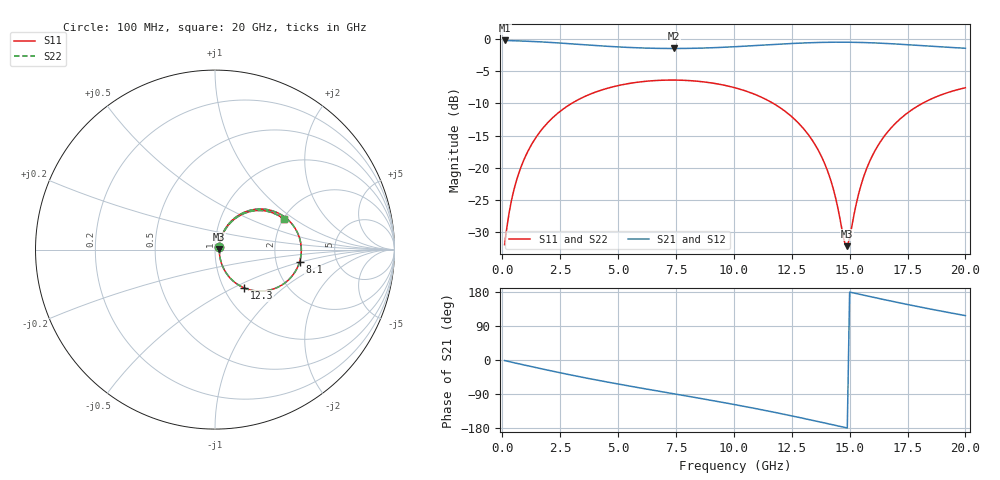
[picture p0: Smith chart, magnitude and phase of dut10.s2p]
! Touchstone file exported from HFSS 2026.1.0
!  File:  C:/ffzhzh/LocalFiles/Ansys_Project_Files/temp_test_TSV_RDL_10_1782979604_6388.aedt
!  Generated:  04:17:51 PM Jul  2, 2026
!  Design:  TSV_RDL
!  Project:  temp_test_TSV_RDL_10_1782979604_6388
! Variables:
!  h_bsmrdl = 3.76um
!  h_ox = 20um
!  h_rdl = 5um
!  h_sub = 52.51um
!  h_tmrdl = 3.14um
!  h_tsv = 52.51um
!  h_via = 3um
!  l_bsmrdl = 600.43um
!  l_sub = 4305.38um
!  l_tmrdl = 493.54um
!  m_sub = 200um
!  pitch = 40.17um
!  r_tsv = 4.32um
!  s_tmrdl = 10um
!  w_bsmrdl = 21.22um
!  w_sub = 500um
!  w_tmrdl = 22.09um
!  x_tsv_center1 = 504.585um
!  x_tsv_center2 = 1126.235um
!  x_tsv_center3 = 1641.865um
!  x_tsv_center4 = 2263.515um
!  x_tsv_center5 = 2779.145um
!  x_tsv_center6 = 3400.795um
# GHz S MA R 50.000000
! Terminal data exported
! Port[1] = TM_RDL1_1_T1
! Port[2] = TM_RDL5_1_T1
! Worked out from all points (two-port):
!   200 points, 100 MHz to 20 GHz, reference 50 ohm
!   highest |S21| = -0.19 dB at 100 MHz (marker M1); lowest = -1.4 dB at 7.4 GHz (marker M2)
!   |S21| within 3 dB of the highest: start of sweep to end of sweep
!   lowest |S11| = -32.2 dB at 14.9 GHz (marker M3), VSWR 1.05, Z = 52.5 + j0.289 ohm
!   |S11| at or under -10 dB: start of sweep to 2.993 GHz; 11.71 GHz to 18.14 GHz (6.433 GHz wide, 43.1 % of centre)
!   |S22| runs from -32.1 to -6.4 dB; largest |S21 - S12| = 1.6e-14
!   S11 on the Smith chart (normalised r, x): 100 MHz: 1.04, +0.03; 8.1 GHz: 2.72, -0.49; 12.3 GHz: 1.24, -0.57; 20 GHz: 2.01, +0.83
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0.1  0.02506 31.1  0.9788 -1.5  0.9788 -1.5  0.02506 31.1
! Gamma 0 0 0 0
! Port Impedance 50 0 50 0
0.3  0.04504 54.9  0.9762 -4.3  0.9762 -4.3  0.04504 54.9
0.5  0.06693 61.5  0.9734 -7.1  0.9734 -7.1  0.06693 61.5
1.2  0.1443 63.0  0.9632 -16.6  0.9632 -16.6  0.1443 63.0
2.2  0.247 53.9  0.9419 -29.9  0.9419 -29.9  0.247 53.9
3.5  0.3539 39.5  0.9073 -46.1  0.9073 -46.1  0.3539 39.5
5  0.4355 23.3  0.8717 -63.4  0.8717 -63.4  0.4355 23.3
6.8  0.4787 4.7  0.8489 -82.7  0.8489 -82.7  0.4787 4.7
7.4  0.4809 -1.3  0.8474 -89.1  0.8474 -89.1  0.481 -1.3
8.1  0.4761 -8.4  0.8495 -96.5  0.8495 -96.5  0.4761 -8.4
10.1  0.4164 -29.1  0.8757 -118.4  0.8757 -118.4  0.4165 -29.1
12.3  0.2672 -52.9  0.9228 -144.9  0.9228 -144.9  0.2672 -52.8
13.4  0.162 -63.4  0.9413 -159.2  0.9413 -159.2  0.1621 -63.2
14.1  0.08871 -65.3  0.9478 -168.6  0.9478 -168.6  0.08883 -65.0
14.4  0.05758 -60.2  0.9489 -172.7  0.9489 -172.7  0.05778 -59.7
14.8  0.02539 -18.0  0.9488 -178.1  0.9488 -178.1  0.02588 -17.6
14.9  0.02443 6.5  0.9484 -179.4  0.9484 -179.4  0.02494 6.3
15.4  0.06354 59.5  0.9451 173.8  0.9451 173.8  0.06376 59.1
15.7  0.0945 63.1  0.9419 169.8  0.9419 169.8  0.09466 62.8
16.7  0.1952 58.1  0.925 156.6  0.925 156.6  0.1953 57.9
18.1  0.3135 43.9  0.8926 139.1  0.8926 139.1  0.3136 43.8
20  0.4188 24.0  0.8513 117.2  0.8513 117.2  0.4189 23.9
